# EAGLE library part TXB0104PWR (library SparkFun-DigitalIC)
4-Bit Bi-Directional Level Shifter 1.2V-3.6V (VCCA) to 1.65V-5.5V (VCCB) bi-directional level shifter with auto direction sensing. Max data rate - VCCA 1.8V: 20Mbps (50ns), VCCA 3.3V: 100Mbps (10ns) Digikey: 296-21929-1-ND (TSSOP) IC-11329

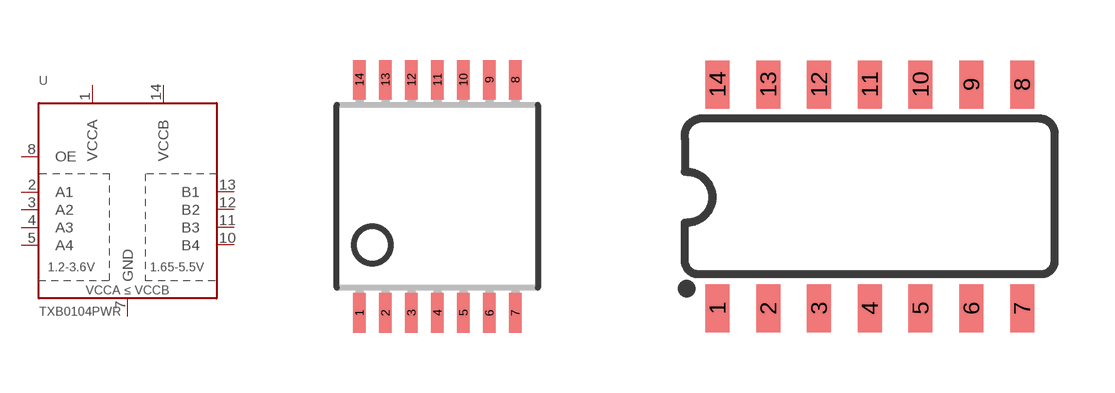
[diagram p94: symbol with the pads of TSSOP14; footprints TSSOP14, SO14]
Designator prefix U

## TXB0104PWR (PROD_ID: IC-11329; VALUE: TXB0104)  [TSSOP14]
1  VCCA
2  A1
3  A2
4  A3
5  A4
7  GND
8  OE
10  B4
11  B3
12  B2
13  B1
14  VCCB

## TXB0104PWRSOIC14 (PROD_ID: IC-11329)  [SO14]
Pads as for TSSOP14

## Footprint TSSOP14 (pad centres in mm)
Thin Shrink Small Outline Plastic 14
smd 0.305 x 0.991: 1 -1.95,-2.918; 2 -1.3,-2.918; 3 -0.65,-2.918; 4 0,-2.918; 5 0.65,-2.918; 6 1.3,-2.918; 7 1.95,-2.918; 8 1.95,2.918; 9 1.3,2.918; 10 0.65,2.918; 11 0,2.918; 12 -0.65,2.918; 13 -1.3,2.918; 14 -1.95,2.918

## Footprint SO14 (pad centres in mm)
smd 0.6 x 1.2: 1 -3.81,-2.8; 2 -2.54,-2.8; 3 -1.27,-2.8; 4 0,-2.8; 5 1.27,-2.8; 6 2.54,-2.8; 7 3.81,-2.8; 8 3.81,2.8; 9 2.54,2.8; 10 1.27,2.8; 11 0,2.8; 12 -1.27,2.8; 13 -2.54,2.8; 14 -3.81,2.8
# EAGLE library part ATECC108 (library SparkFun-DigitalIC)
ATECC108: Provides ECDSA with NIST curves P256, B283, and K283. Also, a RNG, 8.5Kb EEPROM. 2.0V - 5.5V.

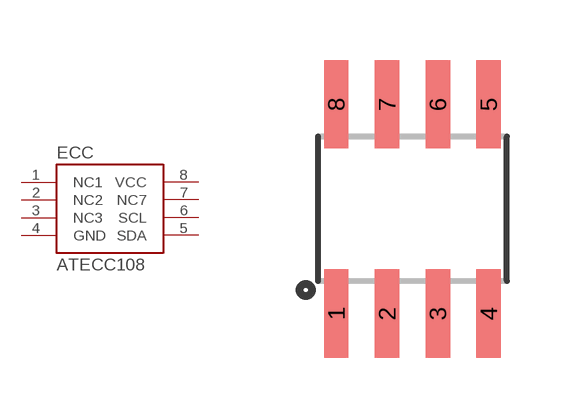
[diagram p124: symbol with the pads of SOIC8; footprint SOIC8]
Designator prefix ECC

## ATECC108 (PROD_ID: IC-11982)  [SOIC8]
1  NC1
2  NC2  nc
3  NC3  nc
4  GND  pwr
5  SDA
6  SCL
7  NC7  nc
8  VCC  pwr

## Footprint SOIC8 (pad centres in mm)
SOIC 8-Lead
smd 0.61 x 2.21: 1 -1.905,-2.616; 2 -0.635,-2.616; 3 0.635,-2.616; 4 1.905,-2.616; 5 1.905,2.616; 6 0.635,2.616; 7 -0.635,2.616; 8 -1.905,2.616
